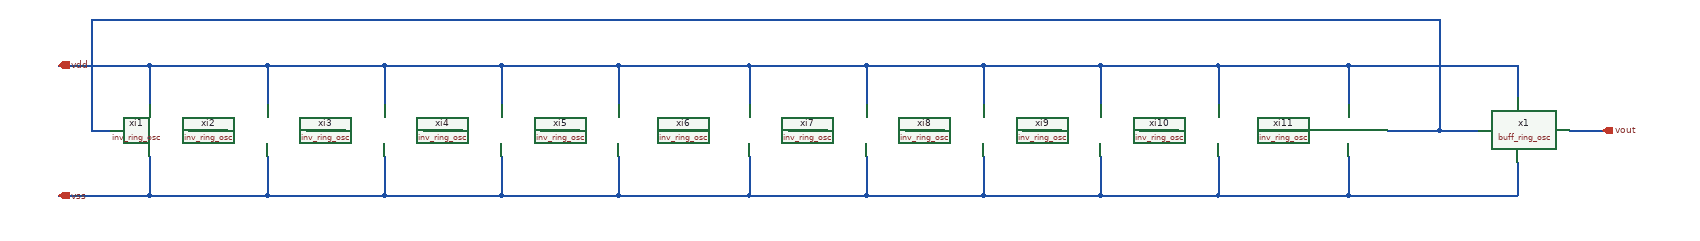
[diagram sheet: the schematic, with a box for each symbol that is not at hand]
v {xschem version=3.4.6 file_version=1.2}
G {}
K {}
V {}
S {}
E {}
N 770 290 770 350 {lab=vss}
N 410 290 410 350 {lab=vss}
N 590 290 590 350 {lab=vss}
N 1330 290 1330 350 {lab=vss}
N 950 290 950 350 {lab=vss}
N 1130 290 1130 350 {lab=vss}
N 1510 290 1510 350 {lab=vss}
N 1130 350 1330 350 {lab=vss}
N 1510 350 1690 350 {lab=vss}
N 950 350 1130 350 {lab=vss}
N 770 350 950 350 {lab=vss}
N 410 350 590 350 {lab=vss}
N 590 350 770 350 {lab=vss}
N 1690 290 1690 350 {lab=vss}
N 1870 290 1870 350 {lab=vss}
N 1870 350 2050 350 {lab=vss}
N 2050 350 2250 350 {lab=vss}
N 2050 290 2050 350 {lab=vss}
N 2590 250 2640 250 {lab=vout}
N 2250 290 2250 350 {lab=vss}
N 2390 80 2390 250 {lab=#net1}
N 1690 350 1870 350 {lab=vss}
N 1750 250 1810 250 {lab=#net2}
N 1570 250 1630 250 {lab=#net3}
N 1390 250 1450 250 {lab=#net4}
N 1330 350 1510 350 {lab=vss}
N 1190 250 1270 250 {lab=#net5}
N 1010 250 1070 250 {lab=#net6}
N 830 250 890 250 {lab=#net7}
N 650 250 710 250 {lab=#net8}
N 470 250 530 250 {lab=#net9}
N 270 350 410 350 {lab=vss}
N 320 250 350 250 {lab=#net1}
N 320 80 320 250 {lab=#net1}
N 2390 250 2450 250 {lab=#net1}
N 2510 300 2510 350 {lab=vss}
N 410 150 410 210 {lab=vdd}
N 590 150 770 150 {lab=vdd}
N 770 150 770 210 {lab=vdd}
N 1130 150 1330 150 {lab=vdd}
N 1330 150 1330 210 {lab=vdd}
N 1870 150 2050 150 {lab=vdd}
N 2050 150 2050 210 {lab=vdd}
N 2510 150 2510 200 {lab=vdd}
N 2250 150 2250 210 {lab=vdd}
N 2050 150 2250 150 {lab=vdd}
N 1870 150 1870 210 {lab=vdd}
N 1690 150 1870 150 {lab=vdd}
N 1510 150 1510 210 {lab=vdd}
N 1330 150 1510 150 {lab=vdd}
N 1690 150 1690 210 {lab=vdd}
N 1510 150 1690 150 {lab=vdd}
N 1130 150 1130 210 {lab=vdd}
N 950 150 1130 150 {lab=vdd}
N 950 150 950 210 {lab=vdd}
N 770 150 950 150 {lab=vdd}
N 590 150 590 210 {lab=vdd}
N 410 150 590 150 {lab=vdd}
N 270 150 410 150 {lab=vdd}
N 2110 250 2190 250 {lab=#net10}
N 1930 250 1990 250 {lab=#net11}
N 2310 250 2390 250 {lab=#net1}
N 320 80 2390 80 {lab=#net1}
N 2250 350 2510 350 {lab=vss}
N 2250 150 2510 150 {lab=vdd}
C {iopin.sym} 270 150 0 1 {name=p1 lab=vdd}
C {iopin.sym} 270 350 0 1 {name=p2 lab=vss}
C {opin.sym} 2640 250 0 0 {name=p3 lab=vout}
C {/shared/designs/SSDOR_1.2V_v3/components/cgenerator/inv_ring_osc.sym} 350 300 0 0 {name=xi1}
C {/shared/designs/SSDOR_1.2V_v3/components/cgenerator/inv_ring_osc.sym} 530 300 0 0 {name=xi2}
C {/shared/designs/SSDOR_1.2V_v3/components/cgenerator/inv_ring_osc.sym} 710 300 0 0 {name=xi3}
C {/shared/designs/SSDOR_1.2V_v3/components/cgenerator/inv_ring_osc.sym} 890 300 0 0 {name=xi4}
C {/shared/designs/SSDOR_1.2V_v3/components/cgenerator/inv_ring_osc.sym} 1070 300 0 0 {name=xi5}
C {/shared/designs/SSDOR_1.2V_v3/components/cgenerator/inv_ring_osc.sym} 1270 300 0 0 {name=xi6}
C {/shared/designs/SSDOR_1.2V_v3/components/cgenerator/inv_ring_osc.sym} 1450 300 0 0 {name=xi7}
C {/shared/designs/SSDOR_1.2V_v3/components/cgenerator/inv_ring_osc.sym} 1630 300 0 0 {name=xi8}
C {/shared/designs/SSDOR_1.2V_v3/components/cgenerator/inv_ring_osc.sym} 1810 300 0 0 {name=xi9}
C {/shared/designs/SSDOR_1.2V_v3/components/cgenerator/inv_ring_osc.sym} 1990 300 0 0 {name=xi10}
C {/shared/designs/SSDOR_1.2V_v3/components/cgenerator/inv_ring_osc.sym} 2190 300 0 0 {name=xi11}
C {/shared/designs/SSDOR_1.2V_v3/components/cgenerator/buff_ring_osc.sym} 2450 310 0 0 {name=x1}
